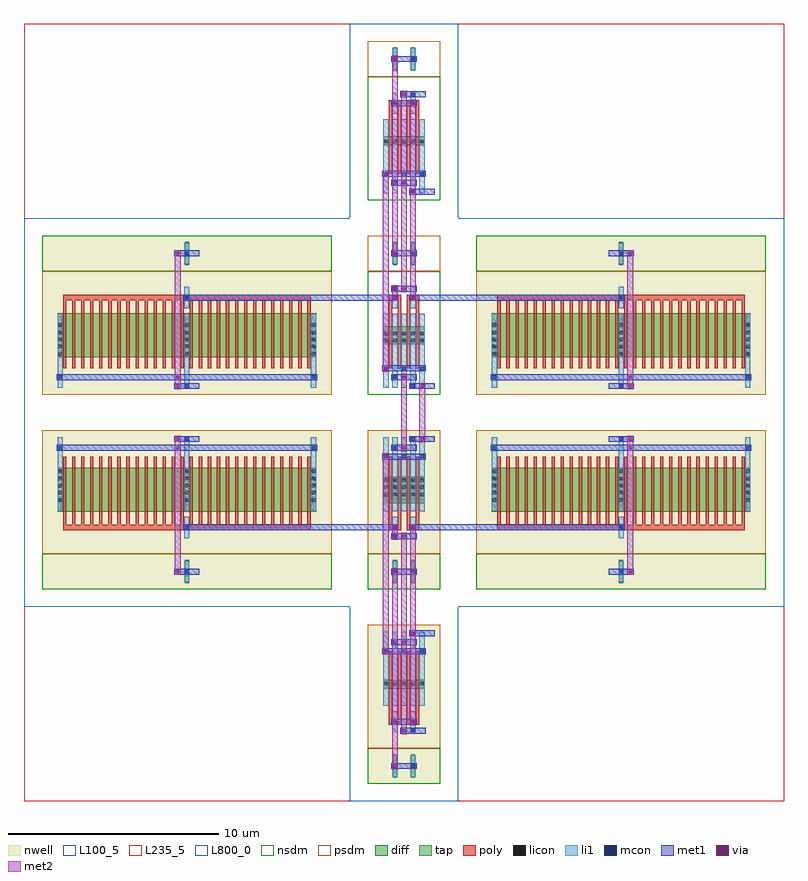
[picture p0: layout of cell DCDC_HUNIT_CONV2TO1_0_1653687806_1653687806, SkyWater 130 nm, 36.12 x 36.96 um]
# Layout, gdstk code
from math import pi, radians
import gdstk
lib = gdstk.Library(unit=1e-6, precision=1e-09)
def R(c, l, rs):  # rectangles x0, y0, x1, y1
    for r in rs: c.add(gdstk.rectangle(r[:2], r[2:], *l))
def A(c, l, x, y, w, h, nx, ny, dx, dy):  # array of equal rectangles
    R(c, l, [(x+i*dx, y+j*dy, x+i*dx+w, y+j*dy+h) for i in range(nx) for j in range(ny)])
def P(c, l, *ps):  # polygons
    for p in ps: c.add(gdstk.Polygon(p, *l))
nwell = (64, 20)
diff = (65, 20)
tap = (65, 44)
poly = (66, 20)
licon = (66, 44)
li1 = (67, 20)
mcon = (67, 44)
met1 = (68, 20)
via = (68, 44)
met2 = (69, 20)
nsdm = (93, 44)
psdm = (94, 20)
L100_5 = (100, 5)
L235_5 = (235, 5)
L800_0 = (800, 0)

ccp_pmos_b_53083828_x1_y = lib.new_cell('CCP_PMOS_B_53083828_X1_Y1_1653687799_1653687802_1653687806_1653687806')
R(ccp_pmos_b_53083828_x1_y, nwell, [(0.86,0.84,4.3,8.4)])
R(ccp_pmos_b_53083828_x1_y, diff, [(1.595,3.465,3.565,3.885)])
R(ccp_pmos_b_53083828_x1_y, tap, [(2.065,7,2.235,8.12), (2.925,7,3.095,8.12)])
A(ccp_pmos_b_53083828_x1_y, poly, 1.86, 2.1, 0.15, 3.36, 4, 1, 0.43, 0)
R(ccp_pmos_b_53083828_x1_y, poly, [(1.86,5.325,2.44,5.595), (2.72,5.325,3.3,5.595)])
A(ccp_pmos_b_53083828_x1_y, licon, 1.635, 3.545, 0.17, 0.17, 3, 1, 0.43, 0)
A(ccp_pmos_b_53083828_x1_y, licon, 2.495, 3.545, 0.17, 0.17, 3, 1, 0.43, 0)
R(ccp_pmos_b_53083828_x1_y, licon, [(2.065,5.375,2.235,5.545), (2.925,5.375,3.095,5.545), (2.065,7.475,2.235,7.645), (2.925,7.475,3.095,7.645)])
A(ccp_pmos_b_53083828_x1_y, li1, 1.595, 1.175, 0.25, 3.53, 5, 1, 0.43, 0)
R(ccp_pmos_b_53083828_x1_y, li1, [(2.025,4.955,2.275,5.965), (2.885,4.955,3.135,5.965), (2.025,7.055,2.275,8.065), (2.885,7.055,3.135,8.065)])
A(ccp_pmos_b_53083828_x1_y, mcon, 1.635, 2.015, 0.17, 0.17, 3, 1, 0.86, 0)
R(ccp_pmos_b_53083828_x1_y, mcon, [(2.065,1.175,2.235,1.345), (2.925,1.595,3.095,1.765), (2.925,5.375,3.095,5.545), (2.065,5.795,2.235,5.965), (2.065,7.475,2.235,7.645), (2.925,7.475,3.095,7.645)])
R(ccp_pmos_b_53083828_x1_y, met1, [(1.12,1.12,2.32,1.4), (1.98,1.54,3.18,1.82), (1.55,1.96,3.61,2.24), (1.98,5.32,3.18,5.6), (1.55,5.74,2.75,6.02), (1.98,7.42,3.18,7.7)])
R(ccp_pmos_b_53083828_x1_y, via, [(2.075,1.185,2.225,1.335), (2.505,1.605,2.655,1.755), (2.075,5.385,2.225,5.535), (2.505,5.805,2.655,5.955)])
R(ccp_pmos_b_53083828_x1_y, met2, [(2.01,1.1,2.29,5.62), (2.44,1.52,2.72,6.04)])
R(ccp_pmos_b_53083828_x1_y, nsdm, [(0.86,6.72,4.3,8.4)])
R(ccp_pmos_b_53083828_x1_y, psdm, [(0.86,0.84,4.3,6.72)])
R(ccp_pmos_b_53083828_x1_y, L100_5, [(0,0,5.16,9.24)])
R(ccp_pmos_b_53083828_x1_y, L800_0, [(0,0,5.16,9.24)])

dp_pmos_b_25364157_x1_y1 = lib.new_cell('DP_PMOS_B_25364157_X1_Y1_1653687801_1653687802_1653687806_1653687806')
R(dp_pmos_b_25364157_x1_y1, nwell, [(0.86,0.84,4.3,8.4)])
R(dp_pmos_b_25364157_x1_y1, diff, [(1.595,3.045,3.565,4.305)])
R(dp_pmos_b_25364157_x1_y1, tap, [(2.065,7,2.235,8.12), (2.925,7,3.095,8.12)])
A(dp_pmos_b_25364157_x1_y1, poly, 1.86, 2.1, 0.15, 3.36, 4, 1, 0.43, 0)
R(dp_pmos_b_25364157_x1_y1, poly, [(1.86,5.325,2.44,5.595), (2.72,5.325,3.3,5.595)])
A(dp_pmos_b_25364157_x1_y1, licon, 1.635, 3.125, 0.17, 0.17, 3, 3, 0.43, 0.34)
A(dp_pmos_b_25364157_x1_y1, licon, 2.495, 3.125, 0.17, 0.17, 3, 3, 0.43, 0.34)
R(dp_pmos_b_25364157_x1_y1, licon, [(2.065,5.375,2.235,5.545), (2.925,5.375,3.095,5.545), (2.065,7.475,2.235,7.645), (2.925,7.475,3.095,7.645)])
A(dp_pmos_b_25364157_x1_y1, li1, 1.595, 1.175, 0.25, 3.53, 5, 1, 0.43, 0)
R(dp_pmos_b_25364157_x1_y1, li1, [(2.025,4.955,2.275,5.965), (2.885,4.955,3.135,5.965), (2.025,7.055,2.275,8.065), (2.885,7.055,3.135,8.065)])
A(dp_pmos_b_25364157_x1_y1, mcon, 1.635, 2.015, 0.17, 0.17, 3, 1, 0.86, 0)
R(dp_pmos_b_25364157_x1_y1, mcon, [(2.065,1.175,2.235,1.345), (2.925,1.595,3.095,1.765), (2.065,5.375,2.235,5.545), (2.925,5.795,3.095,5.965), (2.065,7.475,2.235,7.645), (2.925,7.475,3.095,7.645)])
R(dp_pmos_b_25364157_x1_y1, met1, [(1.12,1.12,2.32,1.4), (1.98,1.54,3.18,1.82), (1.55,1.96,3.61,2.24), (1.12,5.32,2.32,5.6), (1.98,5.74,3.18,6.02), (1.98,7.42,3.18,7.7)])
R(dp_pmos_b_25364157_x1_y1, nsdm, [(0.86,6.72,4.3,8.4)])
R(dp_pmos_b_25364157_x1_y1, psdm, [(0.86,0.84,4.3,6.72)])
R(dp_pmos_b_25364157_x1_y1, L100_5, [(0,0,5.16,9.24)])
R(dp_pmos_b_25364157_x1_y1, L800_0, [(0,0,5.16,9.24)])

dcap_pmos_57222488_x1_y1 = lib.new_cell('DCAP_PMOS_57222488_X1_Y1_1653687800_1653687802_1653687806_1653687806')
R(dcap_pmos_57222488_x1_y1, nwell, [(0.86,0.84,14.62,8.4)])
R(dcap_pmos_57222488_x1_y1, diff, [(1.595,2.625,13.885,4.725)])
R(dcap_pmos_57222488_x1_y1, tap, [(7.655,7,7.825,8.12)])
A(dcap_pmos_57222488_x1_y1, poly, 1.86, 2.1, 0.15, 3.36, 28, 1, 0.43, 0)
R(dcap_pmos_57222488_x1_y1, poly, [(1.86,5.325,13.62,5.595)])
A(dcap_pmos_57222488_x1_y1, licon, 1.635, 2.705, 0.17, 0.17, 3, 5, 6.02, 0.34)
R(dcap_pmos_57222488_x1_y1, licon, [(7.655,5.375,7.825,5.545), (7.655,7.475,7.825,7.645)])
A(dcap_pmos_57222488_x1_y1, li1, 1.595, 1.175, 0.25, 3.53, 3, 1, 6.02, 0)
R(dcap_pmos_57222488_x1_y1, li1, [(7.615,4.955,7.865,5.965), (7.615,7.055,7.865,8.065)])
R(dcap_pmos_57222488_x1_y1, mcon, [(7.655,1.175,7.825,1.345), (1.635,1.595,1.805,1.765), (13.675,1.595,13.845,1.765), (7.655,5.375,7.825,5.545), (7.655,7.475,7.825,7.645)])
R(dcap_pmos_57222488_x1_y1, met1, [(7.14,1.12,8.34,1.4), (1.55,1.54,13.93,1.82), (6.71,5.32,7.91,5.6), (7.14,7.42,8.34,7.7)])
R(dcap_pmos_57222488_x1_y1, via, [(8.095,1.185,8.245,1.335), (8.095,1.605,8.245,1.755), (8.095,7.485,8.245,7.635)])
R(dcap_pmos_57222488_x1_y1, met2, [(8.03,1.1,8.31,7.72)])
R(dcap_pmos_57222488_x1_y1, nsdm, [(0.86,6.72,14.62,8.4)])
R(dcap_pmos_57222488_x1_y1, psdm, [(0.86,0.84,14.62,6.72)])
R(dcap_pmos_57222488_x1_y1, L100_5, [(0,0,15.48,9.24)])
R(dcap_pmos_57222488_x1_y1, L800_0, [(0,0,15.48,9.24)])

dcdc_xsw_pmos_0_16536878 = lib.new_cell('DCDC_XSW_PMOS_0_1653687802_1653687806_1653687806')
R(dcdc_xsw_pmos_0_16536878, met1, [(17.47,1.54,17.79,1.82), (17.47,1.54,17.79,1.82), (17.04,7,17.36,7.28), (17.04,7,17.36,7.28), (17.47,10.78,17.79,11.06), (17.47,10.78,17.79,11.06), (17.47,12.46,17.79,12.74), (17.47,12.46,17.79,12.74), (17.9,12.46,18.22,12.74), (17.9,12.46,18.22,12.74), (17.9,12.46,18.22,12.74), (17.9,12.46,18.22,12.74), (8.6,12.88,17.63,13.16), (17.47,12.88,17.79,13.16), (17.47,12.88,17.79,13.16), (18.33,12.88,18.65,13.16), (18.33,12.88,18.65,13.16), (18.33,12.88,18.65,13.16), (18.33,12.88,18.65,13.16), (19.35,12.88,27.52,13.16), (17.04,16.24,17.36,16.52), (17.04,16.24,17.36,16.52)])
P(dcdc_xsw_pmos_0_16536878, met1, [(0,0),(0,0),(0,0),(0,0)],
  [(0,0),(0,0),(0,0),(0,0)],
  [(0,0),(0,0),(0,0),(0,0)],
  [(0,0),(0,0),(0,0),(0,0)],
  [(0,0),(0,0),(0,0),(0,0)],
  [(0,0),(0,0),(0,0),(0,0)],
  [(0,0),(0,0),(0,0),(0,0)],
  [(0,0),(0,0),(0,0),(0,0)],
  [(0,0),(0,0),(0,0),(0,0)],
  [(0,0),(0,0),(0,0),(0,0)])
R(dcdc_xsw_pmos_0_16536878, via, [(17.555,1.605,17.705,1.755), (17.555,1.605,17.705,1.755), (17.125,7.065,17.275,7.215), (17.125,7.065,17.275,7.215), (17.555,10.845,17.705,10.995), (17.555,10.845,17.705,10.995), (17.555,12.525,17.705,12.675), (17.555,12.525,17.705,12.675), (17.985,12.525,18.135,12.675), (17.985,12.525,18.135,12.675), (17.985,12.525,18.135,12.675), (17.985,12.525,18.135,12.675), (17.555,12.945,17.705,13.095), (17.555,12.945,17.705,13.095), (18.415,12.945,18.565,13.095), (18.415,12.945,18.565,13.095), (18.415,12.945,18.565,13.095), (18.415,12.945,18.565,13.095), (17.125,16.305,17.275,16.455), (17.125,16.305,17.275,16.455)])
R(dcdc_xsw_pmos_0_16536878, met2, [(17.49,1.52,17.77,1.84), (17.49,1.52,17.77,1.84), (17.49,1.68,17.77,10.92), (17.06,6.98,17.34,7.3), (17.06,6.98,17.34,7.3), (17.06,7.14,17.34,16.38), (17.92,7.56,18.2,12.6), (18.35,7.98,18.63,13.02), (17.49,10.76,17.77,11.08), (17.49,10.76,17.77,11.08), (17.49,12.44,17.77,12.76), (17.49,12.44,17.77,12.76), (17.92,12.44,18.2,12.76), (17.92,12.44,18.2,12.76), (17.92,12.44,18.2,12.76), (17.92,12.44,18.2,12.76), (17.49,12.6,17.77,13.02), (17.49,12.86,17.77,13.18), (17.49,12.86,17.77,13.18), (18.35,12.86,18.63,13.18), (18.35,12.86,18.63,13.18), (18.35,12.86,18.63,13.18), (18.35,12.86,18.63,13.18), (17.06,16.22,17.34,16.54), (17.06,16.22,17.34,16.54)])
P(dcdc_xsw_pmos_0_16536878, met2, [(0,0),(0,0),(0,0),(0,0)],
  [(0,0),(0,0),(0,0),(0,0)],
  [(0,0),(0,0),(0,0),(0,0)],
  [(0,0),(0,0),(0,0),(0,0)])
R(dcdc_xsw_pmos_0_16536878, L235_5, [(0,0,36.12,18.48)])
dcdc_xsw_pmos_0_16536878.add(gdstk.Reference(ccp_pmos_b_53083828_x1_y, (20.64,9.24), rotation=pi))
dcdc_xsw_pmos_0_16536878.add(gdstk.Reference(dp_pmos_b_25364157_x1_y1, (20.64,18.48), rotation=pi))
dcdc_xsw_pmos_0_16536878.add(gdstk.Reference(dcap_pmos_57222488_x1_y1, (20.64,18.48), x_reflection=True))
dcdc_xsw_pmos_0_16536878.add(gdstk.Reference(dcap_pmos_57222488_x1_y1, (15.48,18.48), rotation=pi))

ccp_nmos_b_26073270_x1_y = lib.new_cell('CCP_NMOS_B_26073270_X1_Y1_1653687800_1653687801_1653687806_1653687806')
R(ccp_nmos_b_26073270_x1_y, diff, [(1.595,3.465,3.565,3.885)])
R(ccp_nmos_b_26073270_x1_y, tap, [(2.065,7,2.235,8.12), (2.925,7,3.095,8.12)])
A(ccp_nmos_b_26073270_x1_y, poly, 1.86, 2.1, 0.15, 3.36, 4, 1, 0.43, 0)
R(ccp_nmos_b_26073270_x1_y, poly, [(1.86,5.325,2.44,5.595), (2.72,5.325,3.3,5.595)])
A(ccp_nmos_b_26073270_x1_y, licon, 1.635, 3.545, 0.17, 0.17, 3, 1, 0.43, 0)
A(ccp_nmos_b_26073270_x1_y, licon, 2.495, 3.545, 0.17, 0.17, 3, 1, 0.43, 0)
R(ccp_nmos_b_26073270_x1_y, licon, [(2.065,5.375,2.235,5.545), (2.925,5.375,3.095,5.545), (2.065,7.475,2.235,7.645), (2.925,7.475,3.095,7.645)])
A(ccp_nmos_b_26073270_x1_y, li1, 1.595, 1.175, 0.25, 3.53, 5, 1, 0.43, 0)
R(ccp_nmos_b_26073270_x1_y, li1, [(2.025,4.955,2.275,5.965), (2.885,4.955,3.135,5.965), (2.025,7.055,2.275,8.065), (2.885,7.055,3.135,8.065)])
A(ccp_nmos_b_26073270_x1_y, mcon, 1.635, 2.015, 0.17, 0.17, 3, 1, 0.86, 0)
R(ccp_nmos_b_26073270_x1_y, mcon, [(2.065,1.175,2.235,1.345), (2.925,1.595,3.095,1.765), (2.925,5.375,3.095,5.545), (2.065,5.795,2.235,5.965), (2.065,7.475,2.235,7.645), (2.925,7.475,3.095,7.645)])
R(ccp_nmos_b_26073270_x1_y, met1, [(1.12,1.12,2.32,1.4), (1.98,1.54,3.18,1.82), (1.55,1.96,3.61,2.24), (1.98,5.32,3.18,5.6), (1.55,5.74,2.75,6.02), (1.98,7.42,3.18,7.7)])
R(ccp_nmos_b_26073270_x1_y, via, [(2.075,1.185,2.225,1.335), (2.505,1.605,2.655,1.755), (2.075,5.385,2.225,5.535), (2.505,5.805,2.655,5.955)])
R(ccp_nmos_b_26073270_x1_y, met2, [(2.01,1.1,2.29,5.62), (2.44,1.52,2.72,6.04)])
R(ccp_nmos_b_26073270_x1_y, nsdm, [(0.86,0.84,4.3,6.72)])
R(ccp_nmos_b_26073270_x1_y, psdm, [(0.86,6.72,4.3,8.4)])
R(ccp_nmos_b_26073270_x1_y, L100_5, [(0,0,5.16,9.24)])
R(ccp_nmos_b_26073270_x1_y, L800_0, [(0,0,5.16,9.24)])

dp_nmos_b_83449181_x1_y1 = lib.new_cell('DP_NMOS_B_83449181_X1_Y1_1653687802_1653687801_1653687806_1653687806')
R(dp_nmos_b_83449181_x1_y1, diff, [(1.595,3.255,3.565,4.095)])
R(dp_nmos_b_83449181_x1_y1, tap, [(2.065,7,2.235,8.12), (2.925,7,3.095,8.12)])
A(dp_nmos_b_83449181_x1_y1, poly, 1.86, 2.1, 0.15, 3.36, 4, 1, 0.43, 0)
R(dp_nmos_b_83449181_x1_y1, poly, [(1.86,5.325,2.44,5.595), (2.72,5.325,3.3,5.595)])
A(dp_nmos_b_83449181_x1_y1, licon, 1.635, 3.335, 0.17, 0.17, 3, 2, 0.43, 0.34)
A(dp_nmos_b_83449181_x1_y1, licon, 2.495, 3.335, 0.17, 0.17, 3, 2, 0.43, 0.34)
R(dp_nmos_b_83449181_x1_y1, licon, [(2.065,5.375,2.235,5.545), (2.925,5.375,3.095,5.545), (2.065,7.475,2.235,7.645), (2.925,7.475,3.095,7.645)])
A(dp_nmos_b_83449181_x1_y1, li1, 1.595, 1.175, 0.25, 3.53, 5, 1, 0.43, 0)
R(dp_nmos_b_83449181_x1_y1, li1, [(2.025,4.955,2.275,5.965), (2.885,4.955,3.135,5.965), (2.025,7.055,2.275,8.065), (2.885,7.055,3.135,8.065)])
A(dp_nmos_b_83449181_x1_y1, mcon, 1.635, 2.015, 0.17, 0.17, 3, 1, 0.86, 0)
R(dp_nmos_b_83449181_x1_y1, mcon, [(2.065,1.175,2.235,1.345), (2.925,1.595,3.095,1.765), (2.065,5.375,2.235,5.545), (2.925,5.795,3.095,5.965), (2.065,7.475,2.235,7.645), (2.925,7.475,3.095,7.645)])
R(dp_nmos_b_83449181_x1_y1, met1, [(1.12,1.12,2.32,1.4), (1.98,1.54,3.18,1.82), (1.55,1.96,3.61,2.24), (1.12,5.32,2.32,5.6), (1.98,5.74,3.18,6.02), (1.98,7.42,3.18,7.7)])
R(dp_nmos_b_83449181_x1_y1, nsdm, [(0.86,0.84,4.3,6.72)])
R(dp_nmos_b_83449181_x1_y1, psdm, [(0.86,6.72,4.3,8.4)])
R(dp_nmos_b_83449181_x1_y1, L100_5, [(0,0,5.16,9.24)])
R(dp_nmos_b_83449181_x1_y1, L800_0, [(0,0,5.16,9.24)])

c_dcap_pmos_57222488_x1_y1 = lib.new_cell('DCAP_PMOS_57222488_X1_Y1_1653687801_1653687801_1653687806_1653687806')
R(c_dcap_pmos_57222488_x1_y1, nwell, [(0.86,0.84,14.62,8.4)])
R(c_dcap_pmos_57222488_x1_y1, diff, [(1.595,2.625,13.885,4.725)])
R(c_dcap_pmos_57222488_x1_y1, tap, [(7.655,7,7.825,8.12)])
A(c_dcap_pmos_57222488_x1_y1, poly, 1.86, 2.1, 0.15, 3.36, 28, 1, 0.43, 0)
R(c_dcap_pmos_57222488_x1_y1, poly, [(1.86,5.325,13.62,5.595)])
A(c_dcap_pmos_57222488_x1_y1, licon, 1.635, 2.705, 0.17, 0.17, 3, 5, 6.02, 0.34)
R(c_dcap_pmos_57222488_x1_y1, licon, [(7.655,5.375,7.825,5.545), (7.655,7.475,7.825,7.645)])
A(c_dcap_pmos_57222488_x1_y1, li1, 1.595, 1.175, 0.25, 3.53, 3, 1, 6.02, 0)
R(c_dcap_pmos_57222488_x1_y1, li1, [(7.615,4.955,7.865,5.965), (7.615,7.055,7.865,8.065)])
R(c_dcap_pmos_57222488_x1_y1, mcon, [(7.655,1.175,7.825,1.345), (1.635,1.595,1.805,1.765), (13.675,1.595,13.845,1.765), (7.655,5.375,7.825,5.545), (7.655,7.475,7.825,7.645)])
R(c_dcap_pmos_57222488_x1_y1, met1, [(7.14,1.12,8.34,1.4), (1.55,1.54,13.93,1.82), (6.71,5.32,7.91,5.6), (7.14,7.42,8.34,7.7)])
R(c_dcap_pmos_57222488_x1_y1, via, [(8.095,1.185,8.245,1.335), (8.095,1.605,8.245,1.755), (8.095,7.485,8.245,7.635)])
R(c_dcap_pmos_57222488_x1_y1, met2, [(8.03,1.1,8.31,7.72)])
R(c_dcap_pmos_57222488_x1_y1, nsdm, [(0.86,6.72,14.62,8.4)])
R(c_dcap_pmos_57222488_x1_y1, psdm, [(0.86,0.84,14.62,6.72)])
R(c_dcap_pmos_57222488_x1_y1, L100_5, [(0,0,15.48,9.24)])
R(c_dcap_pmos_57222488_x1_y1, L800_0, [(0,0,15.48,9.24)])

dcdc_xsw_nmos_0_16536878 = lib.new_cell('DCDC_XSW_NMOS_0_1653687801_1653687806_1653687806')
R(dcdc_xsw_nmos_0_16536878, met1, [(17.47,1.54,17.79,1.82), (17.47,1.54,17.79,1.82), (17.04,7,17.36,7.28), (17.04,7,17.36,7.28), (17.47,10.78,17.79,11.06), (17.47,10.78,17.79,11.06), (17.47,12.46,17.79,12.74), (17.47,12.46,17.79,12.74), (17.9,12.46,18.22,12.74), (17.9,12.46,18.22,12.74), (17.9,12.46,18.22,12.74), (17.9,12.46,18.22,12.74), (8.6,12.88,17.63,13.16), (17.47,12.88,17.79,13.16), (17.47,12.88,17.79,13.16), (18.33,12.88,18.65,13.16), (18.33,12.88,18.65,13.16), (18.33,12.88,18.65,13.16), (18.33,12.88,18.65,13.16), (19.35,12.88,27.52,13.16), (17.04,16.24,17.36,16.52), (17.04,16.24,17.36,16.52)])
P(dcdc_xsw_nmos_0_16536878, met1, [(0,0),(0,0),(0,0),(0,0)],
  [(0,0),(0,0),(0,0),(0,0)],
  [(0,0),(0,0),(0,0),(0,0)],
  [(0,0),(0,0),(0,0),(0,0)],
  [(0,0),(0,0),(0,0),(0,0)],
  [(0,0),(0,0),(0,0),(0,0)],
  [(0,0),(0,0),(0,0),(0,0)],
  [(0,0),(0,0),(0,0),(0,0)],
  [(0,0),(0,0),(0,0),(0,0)],
  [(0,0),(0,0),(0,0),(0,0)])
R(dcdc_xsw_nmos_0_16536878, via, [(17.555,1.605,17.705,1.755), (17.555,1.605,17.705,1.755), (17.125,7.065,17.275,7.215), (17.125,7.065,17.275,7.215), (17.555,10.845,17.705,10.995), (17.555,10.845,17.705,10.995), (17.555,12.525,17.705,12.675), (17.555,12.525,17.705,12.675), (17.985,12.525,18.135,12.675), (17.985,12.525,18.135,12.675), (17.985,12.525,18.135,12.675), (17.985,12.525,18.135,12.675), (17.555,12.945,17.705,13.095), (17.555,12.945,17.705,13.095), (18.415,12.945,18.565,13.095), (18.415,12.945,18.565,13.095), (18.415,12.945,18.565,13.095), (18.415,12.945,18.565,13.095), (17.125,16.305,17.275,16.455), (17.125,16.305,17.275,16.455)])
R(dcdc_xsw_nmos_0_16536878, met2, [(17.49,1.52,17.77,1.84), (17.49,1.52,17.77,1.84), (17.49,1.68,17.77,10.92), (17.06,6.98,17.34,7.3), (17.06,6.98,17.34,7.3), (17.06,7.14,17.34,16.38), (17.92,7.56,18.2,12.6), (18.35,7.98,18.63,13.02), (17.49,10.76,17.77,11.08), (17.49,10.76,17.77,11.08), (17.49,12.44,17.77,12.76), (17.49,12.44,17.77,12.76), (17.92,12.44,18.2,12.76), (17.92,12.44,18.2,12.76), (17.92,12.44,18.2,12.76), (17.92,12.44,18.2,12.76), (17.49,12.6,17.77,13.02), (17.49,12.86,17.77,13.18), (17.49,12.86,17.77,13.18), (18.35,12.86,18.63,13.18), (18.35,12.86,18.63,13.18), (18.35,12.86,18.63,13.18), (18.35,12.86,18.63,13.18), (17.06,16.22,17.34,16.54), (17.06,16.22,17.34,16.54)])
P(dcdc_xsw_nmos_0_16536878, met2, [(0,0),(0,0),(0,0),(0,0)],
  [(0,0),(0,0),(0,0),(0,0)],
  [(0,0),(0,0),(0,0),(0,0)],
  [(0,0),(0,0),(0,0),(0,0)])
R(dcdc_xsw_nmos_0_16536878, L235_5, [(0,0,36.12,18.48)])
dcdc_xsw_nmos_0_16536878.add(gdstk.Reference(ccp_nmos_b_26073270_x1_y, (20.64,9.24), rotation=pi))
dcdc_xsw_nmos_0_16536878.add(gdstk.Reference(dp_nmos_b_83449181_x1_y1, (20.64,18.48), rotation=pi))
dcdc_xsw_nmos_0_16536878.add(gdstk.Reference(c_dcap_pmos_57222488_x1_y1, (20.64,18.48), x_reflection=True))
dcdc_xsw_nmos_0_16536878.add(gdstk.Reference(c_dcap_pmos_57222488_x1_y1, (15.48,18.48), rotation=pi))

dcdc_hunit_conv2to1_0_16 = lib.new_cell('DCDC_HUNIT_CONV2TO1_0_1653687806_1653687806')
R(dcdc_hunit_conv2to1_0_16, met1, [(17.9,16.66,18.22,16.94), (17.9,16.66,18.22,16.94), (18.76,17.08,19.08,17.36), (18.76,17.08,19.08,17.36), (18.76,19.6,19.08,19.88), (18.76,19.6,19.08,19.88), (17.9,20.02,18.22,20.3), (17.9,20.02,18.22,20.3)])
P(dcdc_hunit_conv2to1_0_16, met1, [(0,0),(0,0),(0,0),(0,0)],
  [(0,0),(0,0),(0,0),(0,0)],
  [(0,0),(0,0),(0,0),(0,0)],
  [(0,0),(0,0),(0,0),(0,0)],
  [(0,0),(0,0),(0,0),(0,0)],
  [(0,0),(0,0),(0,0),(0,0)],
  [(0,0),(0,0),(0,0),(0,0)],
  [(0,0),(0,0),(0,0),(0,0)],
  [(0,0),(0,0),(0,0),(0,0)],
  [(0,0),(0,0),(0,0),(0,0)],
  [(0,0),(0,0),(0,0),(0,0)],
  [(0,0),(0,0),(0,0),(0,0)],
  [(0,0),(0,0),(0,0),(0,0)],
  [(0,0),(0,0),(0,0),(0,0)],
  [(0,0),(0,0),(0,0),(0,0)],
  [(0,0),(0,0),(0,0),(0,0)],
  [(0,0),(0,0),(0,0),(0,0)],
  [(0,0),(0,0),(0,0),(0,0)],
  [(0,0),(0,0),(0,0),(0,0)],
  [(0,0),(0,0),(0,0),(0,0)])
R(dcdc_hunit_conv2to1_0_16, via, [(17.985,16.725,18.135,16.875), (17.985,16.725,18.135,16.875), (18.845,17.145,18.995,17.295), (18.845,17.145,18.995,17.295), (18.845,19.665,18.995,19.815), (18.845,19.665,18.995,19.815), (17.985,20.085,18.135,20.235), (17.985,20.085,18.135,20.235)])
R(dcdc_hunit_conv2to1_0_16, met2, [(17.92,16.64,18.2,16.96), (17.92,16.64,18.2,16.96), (17.92,16.8,18.2,20.16), (18.78,17.06,19.06,17.38), (18.78,17.06,19.06,17.38), (18.78,17.22,19.06,19.74), (18.78,19.58,19.06,19.9), (18.78,19.58,19.06,19.9), (17.92,20,18.2,20.32), (17.92,20,18.2,20.32)])
P(dcdc_hunit_conv2to1_0_16, met2, [(0,0),(0,0),(0,0),(0,0)],
  [(0,0),(0,0),(0,0),(0,0)],
  [(0,0),(0,0),(0,0),(0,0)],
  [(0,0),(0,0),(0,0),(0,0)],
  [(0,0),(0,0),(0,0),(0,0)],
  [(0,0),(0,0),(0,0),(0,0)],
  [(0,0),(0,0),(0,0),(0,0)],
  [(0,0),(0,0),(0,0),(0,0)])
R(dcdc_hunit_conv2to1_0_16, L235_5, [(0,0,36.12,36.96)])
dcdc_hunit_conv2to1_0_16.add(gdstk.Reference(dcdc_xsw_pmos_0_16536878, (0,0)))
dcdc_hunit_conv2to1_0_16.add(gdstk.Reference(dcdc_xsw_nmos_0_16536878, (0,36.96), x_reflection=True))

lib.write_gds('DCDC_HUNIT_CONV2TO1_0_1653687806_1653687806.gds')
